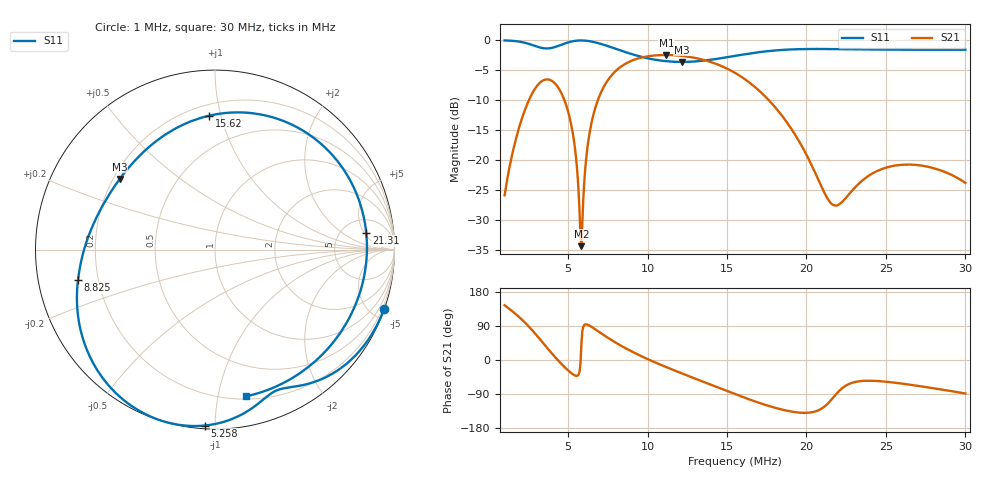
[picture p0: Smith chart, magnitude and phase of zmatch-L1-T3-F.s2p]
# HZ S RI R 50
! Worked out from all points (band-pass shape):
!   505 points, 1 MHz to 30 MHz, reference 50 ohm
!   highest |S21| = -2.44 dB at 11.18 MHz (marker M1); lowest = -34.4 dB at 5.833 MHz (marker M2)
!   |S21| within 3 dB of the highest: 7.868 MHz to 15.51 MHz (7.638 MHz wide, 65.4 % of centre)
!   lowest |S11| = -3.6 dB at 12.16 MHz (marker M3), VSWR 4.89, Z = 11.3 + j15.8 ohm
!   |S11| at or under -10 dB: nowhere
!   S12 and S22 are empty: the file has one direction only
!   S11 on the Smith chart (normalised r, x): 1 MHz: 0.02, -5.84; 5.258 MHz: 0.02, -0.94; 8.825 MHz: 0.12, -0.11; 15.62 MHz: 0.27, +0.92; 21.31 MHz: 8, +6; 30 MHz: 0.22, -1.21
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1000000  0.9419 -0.3324  -0.0413 0.0295  0 0  0 0
2208340  0.6889 -0.6695  -0.0503 0.242  0 0  0 0
3244060  0.4112 -0.768  0.2631 0.3597  0 0  0 0
4107160  0.274 -0.831  0.4367 0.0843  0 0  0 0
5257960  -0.0574 -0.9802  0.143 -0.1056  0 0  0 0
5833360  -0.2934 -0.955  0.0143 0.0126  0 0  0 0
6178600  -0.4249 -0.8965  -0.0076 0.1163  0 0  0 0
6696460  -0.5844 -0.7662  0.0408 0.2668  0 0  0 0
7674640  -0.7432 -0.471  0.2944 0.404  0 0  0 0
8825440  -0.7632 -0.1678  0.5921 0.2938  0 0  0 0
1.066672e7  -0.6577 0.1844  0.741 -0.1286  0 0  0 0
1.118458e7  -0.6168 0.2617  0.7144 -0.2451  0 0  0 0
1.216276e7  -0.5303 0.3941  0.6047 -0.4306  0 0  0 0
1.383142e7  -0.3394 0.5952  0.3049 -0.5954  0 0  0 0
1.550008e7  -0.0555 0.7406  0.000146 -0.5354  0 0  0 0
1.561516e7  -0.0322 0.7461  -0.0165 -0.5241  0 0  0 0
1.774414e7  0.4311 0.695  -0.1648 -0.2562  0 0  0 0
2.033344e7  0.8005 0.28  -0.0669 -0.0604  0 0  0 0
2.131162e7  0.8426 0.0927  -0.0212 -0.043  0 0  0 0
2.20021e7  0.8454 -0.034  0.00446 -0.042  0 0  0 0
2.51668e7  0.6724 -0.4988  0.0463 -0.0743  0 0  0 0
3.000016e7  0.1705 -0.818  0.00178 -0.0644  0 0  0 0
